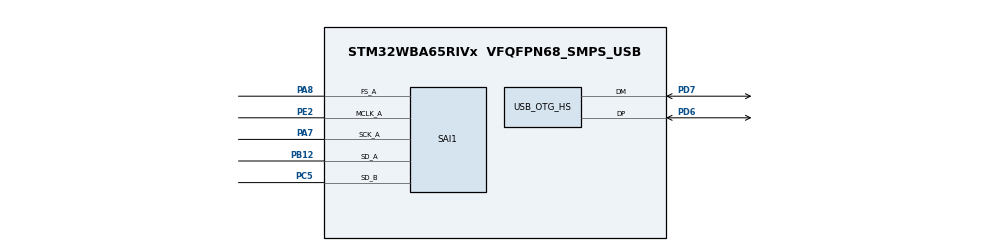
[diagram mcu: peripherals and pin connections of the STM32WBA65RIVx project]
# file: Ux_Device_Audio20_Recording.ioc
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CORTEX_M33_NS.userName=CORTEX_M33
Mcu.Family=STM32WBA
Mcu.Name=STM32WBA65RIVx
Mcu.Package=VFQFPN68_SMPS_USB
NVIC.PriorityGroup=NVIC_PRIORITYGROUP_4
NVIC.TIM17_IRQn=true\:15\:0\:false\:false\:true\:false\:false\:true\:true
NVIC.TimeBase=TIM17_IRQn
NVIC.TimeBaseIP=TIM17
NVIC.USB_OTG_HS_IRQn=true\:7\:0\:true\:false\:true\:false\:false\:true\:true
OSC_IN.Mode=HSE-External-Oscillator
OSC_IN.Signal=RCC_OSC_IN
OSC_OUT.Mode=HSE-External-Oscillator
OSC_OUT.Signal=RCC_OSC_OUT
PA7.Mode=SAI_A_MasterWithClock
PA7.Signal=SAI1_SCK_A
PA8.Mode=SAI_A_MasterWithClock
PA8.Signal=SAI1_FS_A
PB12.Mode=SAI_A_MasterWithClock
PB12.Signal=SAI1_SD_A
PC5.Mode=SAI_B_SyncSlave
PC5.Signal=SAI1_SD_B
PD6.Mode=Internal_Phy_Device
PD6.Signal=USB_OTG_HS_DP
PD7.Mode=Internal_Phy_Device
PD7.Signal=USB_OTG_HS_DM
PE2.Mode=SAI_A_MasterWithClock
PE2.Signal=SAI1_MCLK_A
ProjectManager.HeapSize=0x200
ProjectManager.StackSize=0x400
ProjectManager.TargetToolchain=EWARM V9.60
RCC.ADCFreq_Value=100000000
RCC.AHB5CLKDivider=DIV4
RCC.AHBFreq_Value=100000000
RCC.APB1Freq_Value=100000000
RCC.APB1TimFreq_Value=100000000
RCC.APB2Freq_Value=100000000
RCC.APB2TimFreq_Value=100000000
RCC.CortexFreq_Value=12500000
RCC.HCLKFreq_Value=100000000
RCC.HSE_VALUE=32000000
RCC.HSI_VALUE=16000000
RCC.LSE_VALUE=32768
RCC.LSI1_VALUE=32000
RCC.LSI2_VALUE=32000
RCC.PLLFRACN=4096
RCC.PLLM=2
RCC.PLLN=12
RCC.PLLSourceVirtual=RCC_PLLSOURCE_HSE
RCC.SAI1CLockSelection=RCC_SAI1CLKSOURCE_PLL1P
RCC.SYSCLKFreq_VALUE=100000000
RCC.SYSCLKSourceVirtual=RCC_SYSCLKSOURCE_PLLCLK
RCC.VCOOutputFreq_Value=200000000
SAI1.ActiveFrameLength-SAI_A_MasterWithClock=16
SAI1.ActiveFrameLength-SAI_B_SyncSlave=16
SAI1.AudioFrequency-SAI_A_MasterWithClock=SAI_AUDIO_FREQUENCY_48K
SAI1.AudioMode-SAI_A_MasterWithClock=SAI_MODEMASTER_TX
SAI1.DataSize-SAI_A_MasterWithClock=SAI_DATASIZE_16
SAI1.DataSize-SAI_B_SyncSlave=SAI_DATASIZE_16
SAI1.ErrorAudioFreq-SAI_A_MasterWithClock=1.72 %
SAI1.FrameLength-SAI_A_MasterWithClock=32
SAI1.FrameLength-SAI_B_SyncSlave=32
SAI1.Instance-SAI_A_MasterWithClock=SAI$Index_Block_A
SAI1.Instance-SAI_B_SyncSlave=SAI$Index_Block_B
SAI1.MckOutput=SAI_MCK_OUTPUT_ENABLE
SAI1.MonoStereoMode-SAI_A_MasterWithClock=SAI_STEREOMODE
SAI1.MonoStereoMode-SAI_B_SyncSlave=SAI_MONOMODE
SAI1.NoDivider-SAI_B_SyncSlave=SAI_MASTERDIVIDER_ENABLE
SAI1.OutputDrive-SAI_A_MasterWithClock=SAI_OUTPUTDRIVE_ENABLE
SAI1.OutputDrive-SAI_B_SyncSlave=SAI_OUTPUTDRIVE_ENABLE
SAI1.RealAudioFreq-SAI_A_MasterWithClock=48.828 KHz
SAI1.RealAudioFreq-SAI_B_SyncSlave=500.0 KHz
SAI1.SlotActive-SAI_A_MasterWithClock=0x00000003
SAI1.SlotActive-SAI_B_SyncSlave=0x00000003
SAI1.SlotNumber-SAI_A_MasterWithClock=2
SAI1.SlotNumber-SAI_B_SyncSlave=2
SAI1.VirtualMode-SAI_A_MasterWithClock=VM_MASTER
SAI1.VirtualMode-SAI_B_SyncSlave=VM_SLAVE
SAI1.VirtualSlotActive-SAI_A_MasterWithClock=SAI_SLOT_USERSETTING
SAI1.VirtualSlotActive0-SAI_A_MasterWithClock=true
SAI1.VirtualSlotActive1-SAI_A_MasterWithClock=true
USBX.BSP.number=1
USBX.Core_System=1
USBX.MAX_POWER_IN_MILLI_AMPER=25
USBX.USBD_AUDIO_RECORD_CHANNEL_COUNT=1
USBX.USBD_AUDIO_RECORD_CHANNEL_MAP=1
USBX.USBD_PID=0x5736
USBX.USBD_PRODUCT_STRING=STM32 AUDIO20 RECORDING
USBX.USBD_SERIAL_NUMBER=AUDIO02
USBX.USBD_VID=0x0483
USBX.USBX_DEVICE_APP_THREAD_PRIO=20
USBX.USBX_SYS_SIZE=20 * 1024
USBX.UX_ALIGN_MIN=UX_ALIGN_32
USBX.UX_APP_MEM_POOL_SIZE=53 * 1024
USBX.UX_DEVICE_AUDIO_CORE=1
USBX.UX_DEVICE_AUDIO_RECORDING=1
USBX.UX_DEVICE_ENDPOINT_BUFFER_OWNER=1
USBX.UX_Device_Controller=1
USBX.UX_Device_CoreStack=1
USBX.UX_SLAVE_REQUEST_CONTROL_MAX_LENGTH=512
USBX0.BSP.STBoard=false
USBX0.BSP.api=Unknown
USBX0.BSP.condition=SEMAOoUSBOoOTGOoHSOoDEVICEOoFOROoUSBX
USBX0.BSP.instance=USB_OTG_HS
USBX0.BSP.ip=USB_OTG_HS
USBX0.BSP.mode=Device_Only
USBX0.BSP.name=USB_Device
USBX0.BSP.solution=USB_OTG_HS
USB_OTG_HS.RefClockSelection=SYSCFG_OTG_HS_PHY_CLK_SELECT_6
USB_OTG_HS.Sof_enable=ENABLE
USB_OTG_HS.VirtualMode=Device_HS
VP_CORTEX_M33_NS_VS_Hclk.Mode=Hclk_Mode
VP_ICACHE_VS_ICACHE.Mode=DirectMappedCache
VP_MEMORYMAP_VS_MEMORYMAP.Mode=CurAppReg
VP_PWR_VS_SECSignals.Mode=Security/Privilege
VP_SYS_VS_tim17.Mode=TIM17
VP_THREADX_VS_RTOSJjThreadXJjCoreJjDefault.Mode=Core_Default
VP_USBX_Core_System.Mode=Core_System
VP_USBX_UX\ Device\ AUDIO_HS.Mode=UX_Device_class_AUDIO_HS
VP_USBX_UX\ Device\ AUDIO_RECORDING_HS.Mode=UX_Device_class_AUDIO_RECORDING_HS
VP_USBX_UX\ Device\ Controller_HS.Mode=UX_Device_Controller_HS
VP_USBX_UX\ Device\ CoreStack_HS.Mode=UX_Device_CoreStack_HS
board=custom

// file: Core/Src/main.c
/* USER CODE BEGIN Header */
/**
  ******************************************************************************
  * @file           : main.c
  * @brief          : Main program body
  ******************************************************************************
  * @attention
  *
  * Copyright (c) 2026 STMicroelectronics.
  * All rights reserved.
  *
  * This software is licensed under terms that can be found in the LICENSE file
  * in the root directory of this software component.
  * If no LICENSE file comes with this software, it is provided AS-IS.
  *
  ******************************************************************************
  */
/* USER CODE END Header */
#include "app_threadx.h"
#include "main.h"

SAI_HandleTypeDef hsai_BlockA1;
SAI_HandleTypeDef hsai_BlockB1;

PCD_HandleTypeDef hpcd_USB_OTG_HS;

void SystemClock_Config(void);
static void MX_ICACHE_Init(void);
static void MX_SAI1_Init(void);
/* USER CODE BEGIN PFP */
HAL_StatusTypeDef MX_SAI1_ClockConfig(SAI_HandleTypeDef *hsai, uint32_t SampleRate);

/* USER CODE END PFP */

int main(void)
{

  /* MCU Configuration--------------------------------------------------------*/

  /* Reset of all peripherals, Initializes the Flash interface and the Systick. */
  HAL_Init();

  /* Configure the system clock */
  SystemClock_Config();

  /* Initialize all configured peripherals */
  MX_ICACHE_Init();
  MX_SAI1_Init();

  MX_ThreadX_Init();

  /* We should never get here as control is now taken by the scheduler */

  /* Infinite loop */
  while (1)
  {

  }
}

void SystemClock_Config(void)
{
  RCC_OscInitTypeDef RCC_OscInitStruct = {0};
  RCC_ClkInitTypeDef RCC_ClkInitStruct = {0};

  /** Supply configuration update enable
  */
  HAL_PWREx_ConfigSupply(PWR_LDO_SUPPLY);

  /** Configure the main internal regulator output voltage
  */
  if (HAL_PWREx_ControlVoltageScaling(PWR_REGULATOR_VOLTAGE_SCALE1) != HAL_OK)
  {
    Error_Handler();
  }

  /** Initializes the CPU, AHB and APB busses clocks
  */
  RCC_OscInitStruct.OscillatorType = RCC_OSCILLATORTYPE_HSI|RCC_OSCILLATORTYPE_HSE;
  RCC_OscInitStruct.HSEState = RCC_HSE_ON;
  RCC_OscInitStruct.HSEDiv = RCC_HSE_DIV1;
  RCC_OscInitStruct.HSIState = RCC_HSI_ON;
  RCC_OscInitStruct.HSICalibrationValue = RCC_HSICALIBRATION_DEFAULT;
  RCC_OscInitStruct.PLL1.PLLState = RCC_PLL_ON;
  RCC_OscInitStruct.PLL1.PLLSource = RCC_PLLSOURCE_HSE;
  RCC_OscInitStruct.PLL1.PLLM = 2;
  RCC_OscInitStruct.PLL1.PLLN = 12;
  RCC_OscInitStruct.PLL1.PLLP = 2;
  RCC_OscInitStruct.PLL1.PLLQ = 2;
  RCC_OscInitStruct.PLL1.PLLR = 2;
  RCC_OscInitStruct.PLL1.PLLFractional = 4096;
  if (HAL_RCC_OscConfig(&RCC_OscInitStruct) != HAL_OK)
  {
    Error_Handler();
  }

  /** Initializes the CPU, AHB and APB busses clocks
  */
  RCC_ClkInitStruct.ClockType = RCC_CLOCKTYPE_HCLK|RCC_CLOCKTYPE_SYSCLK
                              |RCC_CLOCKTYPE_PCLK1|RCC_CLOCKTYPE_PCLK2
                              |RCC_CLOCKTYPE_PCLK7|RCC_CLOCKTYPE_HCLK5;
  RCC_ClkInitStruct.SYSCLKSource = RCC_SYSCLKSOURCE_PLLCLK;
  RCC_ClkInitStruct.AHBCLKDivider = RCC_SYSCLK_DIV1;
  RCC_ClkInitStruct.APB1CLKDivider = RCC_HCLK_DIV1;
  RCC_ClkInitStruct.APB2CLKDivider = RCC_HCLK_DIV1;
  RCC_ClkInitStruct.APB7CLKDivider = RCC_HCLK_DIV1;
  RCC_ClkInitStruct.AHB5_PLL1_CLKDivider = RCC_SYSCLK_PLL1_DIV4;
  RCC_ClkInitStruct.AHB5_HSEHSI_CLKDivider = RCC_SYSCLK_HSEHSI_DIV1;

  if (HAL_RCC_ClockConfig(&RCC_ClkInitStruct, FLASH_LATENCY_3) != HAL_OK)
  {
    Error_Handler();
  }
}

static void MX_ICACHE_Init(void)
{

  /** Enable instruction cache in 1-way (direct mapped cache)
  */
  if (HAL_ICACHE_ConfigAssociativityMode(ICACHE_1WAY) != HAL_OK)
  {
    Error_Handler();
  }
  if (HAL_ICACHE_Enable() != HAL_OK)
  {
    Error_Handler();
  }

}

static void MX_SAI1_Init(void)
{

  hsai_BlockA1.Instance = SAI1_Block_A;
  hsai_BlockA1.Init.Protocol = SAI_FREE_PROTOCOL;
  hsai_BlockA1.Init.AudioMode = SAI_MODEMASTER_TX;
  hsai_BlockA1.Init.DataSize = SAI_DATASIZE_16;
  hsai_BlockA1.Init.FirstBit = SAI_FIRSTBIT_MSB;
  hsai_BlockA1.Init.ClockStrobing = SAI_CLOCKSTROBING_FALLINGEDGE;
  hsai_BlockA1.Init.Synchro = SAI_ASYNCHRONOUS;
  hsai_BlockA1.Init.OutputDrive = SAI_OUTPUTDRIVE_ENABLE;
  hsai_BlockA1.Init.NoDivider = SAI_MASTERDIVIDER_ENABLE;
  hsai_BlockA1.Init.FIFOThreshold = SAI_FIFOTHRESHOLD_EMPTY;
  hsai_BlockA1.Init.AudioFrequency = SAI_AUDIO_FREQUENCY_48K;
  hsai_BlockA1.Init.SynchroExt = SAI_SYNCEXT_DISABLE;
  hsai_BlockA1.Init.MckOutput = SAI_MCK_OUTPUT_ENABLE;
  hsai_BlockA1.Init.MonoStereoMode = SAI_STEREOMODE;
  hsai_BlockA1.Init.CompandingMode = SAI_NOCOMPANDING;
  hsai_BlockA1.Init.TriState = SAI_OUTPUT_NOTRELEASED;
  hsai_BlockA1.Init.PdmInit.Activation = DISABLE;
  hsai_BlockA1.Init.PdmInit.MicPairsNbr = 1;
  hsai_BlockA1.Init.PdmInit.ClockEnable = SAI_PDM_CLOCK1_ENABLE;
  hsai_BlockA1.FrameInit.FrameLength = 32;
  hsai_BlockA1.FrameInit.ActiveFrameLength = 16;
  hsai_BlockA1.FrameInit.FSDefinition = SAI_FS_STARTFRAME;
  hsai_BlockA1.FrameInit.FSPolarity = SAI_FS_ACTIVE_LOW;
  hsai_BlockA1.FrameInit.FSOffset = SAI_FS_FIRSTBIT;
  hsai_BlockA1.SlotInit.FirstBitOffset = 0;
  hsai_BlockA1.SlotInit.SlotSize = SAI_SLOTSIZE_DATASIZE;
  hsai_BlockA1.SlotInit.SlotNumber = 2;
  hsai_BlockA1.SlotInit.SlotActive = 0x00000003;
  if (HAL_SAI_Init(&hsai_BlockA1) != HAL_OK)
  {
    Error_Handler();
  }
  hsai_BlockB1.Instance = SAI1_Block_B;
  hsai_BlockB1.Init.Protocol = SAI_FREE_PROTOCOL;
  hsai_BlockB1.Init.AudioMode = SAI_MODESLAVE_RX;
  hsai_BlockB1.Init.DataSize = SAI_DATASIZE_16;
  hsai_BlockB1.Init.FirstBit = SAI_FIRSTBIT_MSB;
  hsai_BlockB1.Init.ClockStrobing = SAI_CLOCKSTROBING_FALLINGEDGE;
  hsai_BlockB1.Init.Synchro = SAI_SYNCHRONOUS;
  hsai_BlockB1.Init.OutputDrive = SAI_OUTPUTDRIVE_ENABLE;
  hsai_BlockB1.Init.NoDivider = SAI_MASTERDIVIDER_ENABLE;
  hsai_BlockB1.Init.FIFOThreshold = SAI_FIFOTHRESHOLD_EMPTY;
  hsai_BlockB1.Init.SynchroExt = SAI_SYNCEXT_DISABLE;
  hsai_BlockB1.Init.MckOutput = SAI_MCK_OUTPUT_ENABLE;
  hsai_BlockB1.Init.MonoStereoMode = SAI_MONOMODE;
  hsai_BlockB1.Init.CompandingMode = SAI_NOCOMPANDING;
  hsai_BlockB1.Init.TriState = SAI_OUTPUT_NOTRELEASED;
  hsai_BlockB1.Init.PdmInit.Activation = DISABLE;
  hsai_BlockB1.Init.PdmInit.MicPairsNbr = 1;
  hsai_BlockB1.Init.PdmInit.ClockEnable = SAI_PDM_CLOCK1_ENABLE;
  hsai_BlockB1.FrameInit.FrameLength = 32;
  hsai_BlockB1.FrameInit.ActiveFrameLength = 16;
  hsai_BlockB1.FrameInit.FSDefinition = SAI_FS_STARTFRAME;
  hsai_BlockB1.FrameInit.FSPolarity = SAI_FS_ACTIVE_LOW;
  hsai_BlockB1.FrameInit.FSOffset = SAI_FS_FIRSTBIT;
  hsai_BlockB1.SlotInit.FirstBitOffset = 0;
  hsai_BlockB1.SlotInit.SlotSize = SAI_SLOTSIZE_DATASIZE;
  hsai_BlockB1.SlotInit.SlotNumber = 2;
  hsai_BlockB1.SlotInit.SlotActive = 0x00000003;
  if (HAL_SAI_Init(&hsai_BlockB1) != HAL_OK)
  {
    Error_Handler();
  }

}

void MX_USB_OTG_HS_PCD_Init(void)
{

  hpcd_USB_OTG_HS.Instance = USB_OTG_HS;
  hpcd_USB_OTG_HS.Init.dev_endpoints = 9;
  hpcd_USB_OTG_HS.Init.speed = PCD_SPEED_HIGH;
  hpcd_USB_OTG_HS.Init.phy_itface = USB_OTG_HS_EMBEDDED_PHY;
  hpcd_USB_OTG_HS.Init.Sof_enable = ENABLE;
  hpcd_USB_OTG_HS.Init.low_power_enable = DISABLE;
  hpcd_USB_OTG_HS.Init.lpm_enable = DISABLE;
  hpcd_USB_OTG_HS.Init.use_dedicated_ep1 = DISABLE;
  hpcd_USB_OTG_HS.Init.vbus_sensing_enable = DISABLE;
  hpcd_USB_OTG_HS.Init.dma_enable = DISABLE;
  if (HAL_PCD_Init(&hpcd_USB_OTG_HS) != HAL_OK)
  {
    Error_Handler();
  }
  /* USER CODE BEGIN USB_OTG_HS_PCD_Init 2 */
  /* Set Rx FIFO */
  HAL_PCDEx_SetRxFiFo(&hpcd_USB_OTG_HS, 0x200);
  /* Set Tx FIFO 0 */
  HAL_PCDEx_SetTxFiFo(&hpcd_USB_OTG_HS, 0, USBD_MAX_EP0_SIZE / 4U);
  /* Set Tx FIFO 1 */
  HAL_PCDEx_SetTxFiFo(&hpcd_USB_OTG_HS, 1, USBD_AUDIO_RECORD_EPIN_HS_MPS / 2U);
  /* USER CODE END USB_OTG_HS_PCD_Init 2 */

}

/* USER CODE BEGIN 4 */

/**
  * @brief  Selects PLL1P as the SAI1 clock source and enables the SAI1 clock.
  * @note   Overrides the BSP weak function without reconfiguring PLL1
  *         or changing SYSCLK. PLL1 must be configured beforehand.
  * @param  hsai: SAI handle.
  * @param  SampleRate: Requested sample rate.
  * @retval HAL status.
  */
HAL_StatusTypeDef MX_SAI1_ClockConfig(SAI_HandleTypeDef *hsai, uint32_t SampleRate)
{
  RCC_PeriphCLKInitTypeDef PeriphClkInit = {0};

  PeriphClkInit.PeriphClockSelection = RCC_PERIPHCLK_SAI1;
  PeriphClkInit.Sai1ClockSelection = RCC_SAI1CLKSOURCE_PLL1P;
  if (HAL_RCCEx_PeriphCLKConfig(&PeriphClkInit) != HAL_OK)
  {
    return HAL_ERROR;
  }

  __HAL_RCC_SAI1_CLK_ENABLE();
  return HAL_OK;
}

/* USER CODE END 4 */

void HAL_TIM_PeriodElapsedCallback(TIM_HandleTypeDef *htim)
{
  if (htim->Instance == TIM17)
  {
    HAL_IncTick();
  }
}

void Error_Handler(void)
{
  while (1)
  {
  }
}
